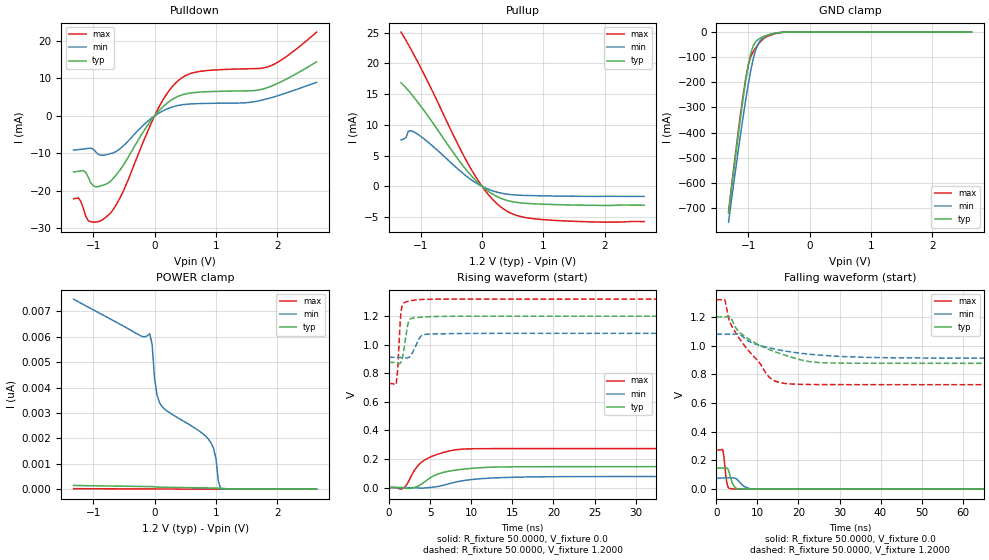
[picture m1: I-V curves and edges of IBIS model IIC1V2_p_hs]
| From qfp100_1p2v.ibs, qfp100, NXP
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[Model] IIC1V2_p_hs
|   Model IIC1V2_p_hs
| This model was characterised for following simulation conditions:
| External (pad) voltage:
|   - Typ: 1.2V,   - Min: 1.08V,   - Max: 1.32V
| Library cells for typ/min/max conditions are connected as defined below:
|  IO - External Pad
|  A - Core Input
|  EN - Output Buffer Enable
|  BOOST - vdde
|  EGP - vdd
|  EHS - vdd
|  ENZI - vdd
|  EPD - gnd
|  EPUN - vdd
|  ZI - NC
|  ZIF - NC
|  gnd - gnd
|  gnde - gnde
|  vdd - vdd
|  vdde - vdde
| All other pins connected to ground
Model_type I/O
Polarity   Non-Inverting
Enable   Active-Low
Vinl =   0.5400V
Vinh =   1.2600V
Vmeas =  0.9000V
Cref =   0.0F
Rref =   1.0000k
Vref =   0.0V
C_comp   3.6473pF   3.5138pF   3.7665pF
|C_comp_pullup   0.9539pF   0.9082pF   0.9728pF
|C_comp_pulldown   2.3399pF   2.4915pF   2.1962pF
[Model Spec]
| variable   typ   min   max
Vinh   0.3600V   0.3240V   0.3960V
Vinl   0.8400V   0.7560V   0.9240V
Vmeas   0.6000V   0.5400V   0.6600V
[Temperature Range]   25.0000   0.1250k   -40.0000
[Voltage Range]   1.2000V   1.0800V   1.3200V
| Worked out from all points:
|   slope of the pulldown table from 0 to 0.18 V, typ, clamps not added: 58.3 ohm
|   slope of the pullup table from 0 to 0.18 V, typ, clamps not added: 138 ohm
|   GND clamp passes 1 mA (typ) near -0.45 V on its own axis
|   rising waveform, R_fixture 50.0000, V_fixture 0.0: 20-80 % time 3.45ns typ, 4.61ns min, 2.73ns max; typ from 0 V to 0.146 V
|   rising waveform, R_fixture 50.0000, V_fixture 1.2000: 20-80 % time 519ps typ, 830ps min, 343ps max; typ from 0.877 V to 1.2 V
|   falling waveform, R_fixture 50.0000, V_fixture 0.0: 20-80 % time 1.02ns typ, 1.79ns min, 624ps max; typ from 0.146 V to 0 V
|   falling waveform, R_fixture 50.0000, V_fixture 1.2000: 20-80 % time 11.4ns typ, 13.9ns min, 8.37ns max; typ from 1.2 V to 0.877 V
[Pulldown]
|Voltage   I(typ)   I(min)   I(max)
-1.32V    -14.96mA   -9.099mA   -22.09mA
-1.24V    -14.75mA   -8.982mA   -21.89mA
-1.16V    -14.56mA   -8.83mA    -24.7mA
-1.04V    -17.82mA   -8.609mA   -28.21mA
-920mV    -18.88mA   -10.21mA   -28.21mA
-720mV    -17.44mA   -10.07mA   -25.94mA
-520mV    -13.41mA   -8.157mA   -20.44mA
80mV      1.521mA    840uA      2.628mA
440mV     5.569mA    2.951mA    10.1mA
760mV     6.377mA    3.307mA    11.92mA
1.84V     7.559mA    4.586mA    13.06mA
2.64V     14.43mA    8.958mA    22.36mA
[Pullup]
|Voltage   I(typ)   I(min)   I(max)
-1.32V    16.87mA    7.562mA    25.11mA
-1.24V    16.04mA    7.944mA    23.76mA
-1.2V     15.58mA    9.001mA    23.05mA
-1.08V    14.1mA     8.693mA    20.85mA
-400mV    4.54mA     2.884mA    6.955mA
-200mV    2.009mA    1.241mA    3.176mA
80mV      -640.3uA   -373.7uA   -1.07mA
320mV     -1.996mA   -1.123mA   -3.467mA
560mV     -2.602mA   -1.412mA   -4.719mA
920mV     -2.876mA   -1.532mA   -5.352mA
1.96V     -3.103mA   -1.628mA   -5.823mA
2.64V     -3.069mA   -1.636mA   -5.736mA
[GND_clamp]
|Voltage   I(typ)   I(min)   I(max)
-1.32V    -720.7mA   -756.4mA   -713.8mA
-1.12V    -330.9mA   -399.5mA   -316.8mA
-1.04V    -192.4mA   -269.2mA   -184.4mA
-1V       -133.6mA   -209.3mA   -133.5mA
-960mV    -86.73mA   -154.7mA   -99.45mA
-920mV    -55.68mA   -108.2mA   -79.01mA
-880mV    -39.01mA   -72.34mA   -63.7mA
-840mV    -29.9mA    -47.99mA   -50.25mA
-760mV    -18.92mA   -23.38mA   -28.31mA
-640mV    -9.212mA   -8.622mA   -12.72mA
-400mV    -328.4uA   -396.6uA   -434.3uA
2.64V     0A         0A         0A
[POWER_clamp]
|Voltage   I(typ)   I(min)   I(max)
-1.32V    146.2pA    7.487nA    20.6pA
-240mV    107.2pA    6.058nA    10.71pA
-80mV     104.3pA    6.128nA    10.43pA
-40mV     105.3pA    5.7nA      9.002pA
0V        87.49pA    4.363nA    8.131pA
80mV      77.4pA     3.412nA    7.54pA
880mV     48.09pA    1.964nA    2.626pA
960mV     44.51pA    1.611nA    2.139pA
1V        42.37pA    1.211nA    1.894pA
1.04V     39.75pA    304.3pA    1.646pA
1.08V     36.09pA    0A         1.394pA
2.64V     0A         0A         0A
[Ramp]
| variable   typ   min   max
dV/dt_r  87.7543m/3.4464n   46.4153m/4.6065n   0.1637/2.7335n
dV/dt_f  0.1940/11.3751n   0.1007/13.8710n   0.3553/8.3673n
R_load = 50.0000
[Rising Waveform]
R_fixture= 50.0000
V_fixture= 0.0
V_fixture_min= 0.0
V_fixture_max= 0.0
|time   V(typ)   V(min)   V(max)
0s        663.7pV    60.46nV    39.17pV
1.735ns   -2.682mV   172.8uV    -4.698mV
2.17ns    -6.221mV   31.22uV    20.88mV
3.005ns   -724.5uV   -2.28mV    111.7mV
3.546ns   10.08mV    -3.777mV   154.7mV
5.333ns   78.4mV     2.145mV    220.8mV
8.076ns   122mV      37.42mV    264mV
11.88ns   140.8mV    64.41mV    272.4mV
33.26ns   146.2mV    77.18mV    272.7mV
1us       146.3mV    77.36mV    272.8mV
[Rising Waveform]
R_fixture= 50.0000
V_fixture= 1.2000
V_fixture_min= 1.0800
V_fixture_max= 1.3200
|time   V(typ)   V(min)   V(max)
0s        876.6mV    912.2mV    727.9mV
925.4ps   873.7mV    912.5mV    744.3mV
1.07ns    870.9mV    912.4mV    833.7mV
1.417ns   872.4mV    910.7mV    1.195V
1.686ns   919.9mV    908.8mV    1.282V
2.223ns   1.121V     906.8mV    1.303V
2.507ns   1.175V     914.8mV    1.307V
3.963ns   1.194V     1.064V     1.317V
5.617ns   1.198V     1.076V     1.319V
1us       1.2V       1.08V      1.32V
[Falling Waveform]
R_fixture= 50.0000
V_fixture= 0.0
V_fixture_min= 0.0
V_fixture_max= 0.0
|time   V(typ)   V(min)   V(max)
0s        146.3mV    77.36mV    272.8mV
1.583ns   146.6mV    77.35mV    269.1mV
1.815ns   147.6mV    77.32mV    228.9mV
2.378ns   149.7mV    77.32mV    73.57mV
2.869ns   135mV      77.95mV    12.66mV
4.132ns   28.89mV    79.27mV    1.543mV
5.749ns   1.763mV    46.03mV    353.1uV
8.143ns   287.7uV    3.769mV    70.4uV
13.48ns   24.82uV    120.4uV    7.14uV
1us       23.59nV    99.24nV    13.67nV
[Falling Waveform]
R_fixture= 50.0000
V_fixture= 1.2000
V_fixture_min= 1.0800
V_fixture_max= 1.3200
|time   V(typ)   V(min)   V(max)
0s        1.2V       1.08V      1.32V
1.968ns   1.2V       1.08V      1.323V
3.029ns   1.203V     1.08V      1.186V
3.948ns   1.169V     1.08V      1.125V
6.283ns   1.078V     1.066V     1.021V
12.91ns   971.7mV    984.4mV    779.2mV
15.66ns   943.4mV    967.9mV    741.4mV
21.16ns   896.8mV    945.1mV    729.9mV
62.12ns   876.8mV    912.9mV    728mV
1us       876.6mV    912.2mV    727.9mV
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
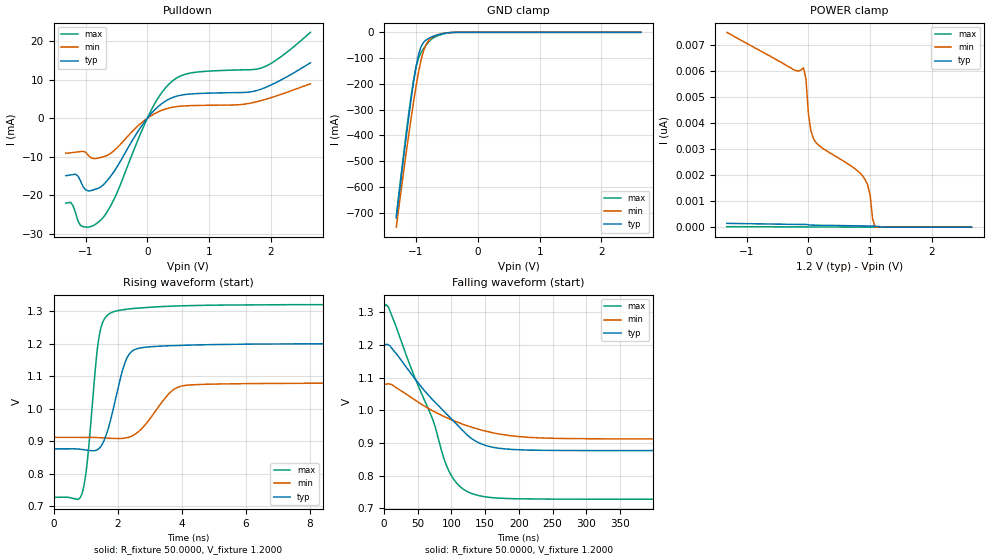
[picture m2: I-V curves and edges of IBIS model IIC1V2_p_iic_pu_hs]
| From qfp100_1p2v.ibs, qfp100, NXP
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[Model] IIC1V2_p_iic_pu_hs
|   Model IIC1V2_p_iic_pu_hs
| This model was characterised for following simulation conditions:
| External (pad) voltage:
|   - Typ: 1.2V,   - Min: 1.08V,   - Max: 1.32V
| Library cells for typ/min/max conditions are connected as defined below:
|  IO - External Pad
|  A - Core Input
|  EN - Output Buffer Enable
|  BOOST - vdde
|  ECS - vdd
|  EGP - gnd
|  ENZI - vdd
|  EPD - gnd
|  EPUN - vdd
|  SSEL - vdd
|  ZI - NC
|  ZIF - NC
|  gnd - gnd
|  gnde - gnde
|  vdd - vdd
|  vdde - vdde
| All other pins connected to ground
Model_type I/O_open_drain
Polarity   Non-Inverting
Enable   Active-Low
Vinl =   0.5400V
Vinh =   1.2600V
Vmeas =  0.9000V
Cref =   0.0F
Rref =   1.0000k
Vref =   1.2000V
C_comp   3.6473pF   3.5138pF   3.7665pF
|C_comp_pullup   0.9537pF   0.9078pF   0.9727pF
|C_comp_pulldown   2.3401pF   2.4920pF   2.1963pF
[Model Spec]
| variable   typ   min   max
Vinh   0.3600V   0.3240V   0.3960V
Vinl   0.8400V   0.7560V   0.9240V
Vmeas   0.6000V   0.5400V   0.6600V
Vref   1.2000V   1.0800V   1.3200V
Cref   0.0F   0.0F   0.0F
Rref   1.0000k   1.0000k   1.0000k
[Temperature Range]   25.0000   0.1250k   -40.0000
[Voltage Range]   1.2000V   1.0800V   1.3200V
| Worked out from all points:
|   slope of the pulldown table from 0 to 0.18 V, typ, clamps not added: 58.3 ohm
|   GND clamp passes 1 mA (typ) near -0.45 V on its own axis
|   rising waveform, R_fixture 50.0000, V_fixture 1.2000: 20-80 % time 494ps typ, 787ps min, 328ps max; typ from 0.877 V to 1.2 V
|   falling waveform, R_fixture 50.0000, V_fixture 1.2000: 20-80 % time 83.3ns typ, 99ns min, 62.7ns max; typ from 1.2 V to 0.877 V
[Pulldown]
|Voltage   I(typ)   I(min)   I(max)
-1.32V    -14.96mA   -9.099mA   -22.09mA
-1.24V    -14.75mA   -8.982mA   -21.89mA
-1.16V    -14.56mA   -8.83mA    -24.7mA
-1.04V    -17.82mA   -8.609mA   -28.21mA
-920mV    -18.88mA   -10.21mA   -28.21mA
-720mV    -17.44mA   -10.07mA   -25.94mA
-520mV    -13.41mA   -8.157mA   -20.44mA
80mV      1.521mA    840uA      2.628mA
440mV     5.569mA    2.951mA    10.1mA
760mV     6.377mA    3.307mA    11.92mA
1.84V     7.559mA    4.586mA    13.06mA
2.64V     14.43mA    8.958mA    22.36mA
[GND_clamp]
|Voltage   I(typ)   I(min)   I(max)
-1.32V    -720.7mA   -756.4mA   -713.8mA
-1.12V    -330.9mA   -399.5mA   -316.8mA
-1.04V    -192.4mA   -269.2mA   -184.4mA
-1V       -133.6mA   -209.3mA   -133.5mA
-960mV    -86.73mA   -154.7mA   -99.45mA
-920mV    -55.68mA   -108.2mA   -79.01mA
-880mV    -39.01mA   -72.34mA   -63.7mA
-840mV    -29.9mA    -47.99mA   -50.25mA
-760mV    -18.92mA   -23.38mA   -28.31mA
-640mV    -9.212mA   -8.622mA   -12.72mA
-400mV    -328.4uA   -396.6uA   -434.3uA
2.64V     0A         0A         0A
[POWER_clamp]
|Voltage   I(typ)   I(min)   I(max)
-1.32V    146.2pA    7.487nA    20.6pA
-240mV    107.2pA    6.058nA    10.71pA
-80mV     104.3pA    6.128nA    10.43pA
-40mV     105.3pA    5.7nA      9.002pA
0V        87.49pA    4.363nA    8.131pA
80mV      77.4pA     3.412nA    7.54pA
880mV     48.09pA    1.964nA    2.626pA
960mV     44.51pA    1.611nA    2.139pA
1V        42.37pA    1.211nA    1.894pA
1.04V     39.75pA    304.3pA    1.646pA
1.08V     36.09pA    0A         1.394pA
2.64V     0A         0A         0A
[Ramp]
| variable   typ   min   max
dV/dt_r  0.1940/0.4944n   0.1007/0.7878n   0.3553/0.3284n
dV/dt_f  0.1940/83.2985n   0.1006/99.0257n   0.3552/62.6594n
R_load = 50.0000
[Rising Waveform]
R_fixture= 50.0000
V_fixture= 1.2000
V_fixture_min= 1.0800
V_fixture_max= 1.3200
|time   V(typ)   V(min)   V(max)
0s        876.6mV    912.2mV    727.9mV
903ps     874.8mV    912.4mV    743.6mV
1.063ns   872.6mV    912.3mV    844.4mV
1.396ns   875.6mV    911.2mV    1.204V
1.672ns   926.9mV    909.9mV    1.286V
2.162ns   1.12V      908.9mV    1.304V
2.467ns   1.178V     917.2mV    1.308V
3.862ns   1.194V     1.065V     1.315V
6.142ns   1.198V     1.077V     1.319V
1us       1.2V       1.08V      1.32V
[Falling Waveform]
R_fixture= 50.0000
V_fixture= 1.2000
V_fixture_min= 1.0800
V_fixture_max= 1.3200
|time   V(typ)   V(min)   V(max)
0s        1.2V       1.08V      1.32V
6.561ns   1.2V       1.081V     1.316V
45.2ns    1.098V     1.032V     1.102V
69.62ns   1.038V     1.002V     985.8mV
95.52ns   983.6mV    975.1mV    817.3mV
112.5ns   947.2mV    961mV      767.4mV
135.3ns   906.9mV    945.2mV    742.1mV
177.8ns   882.4mV    925.3mV    730.9mV
264.1ns   877.4mV    914.1mV    728.5mV
1us       876.7mV    912.3mV    728mV
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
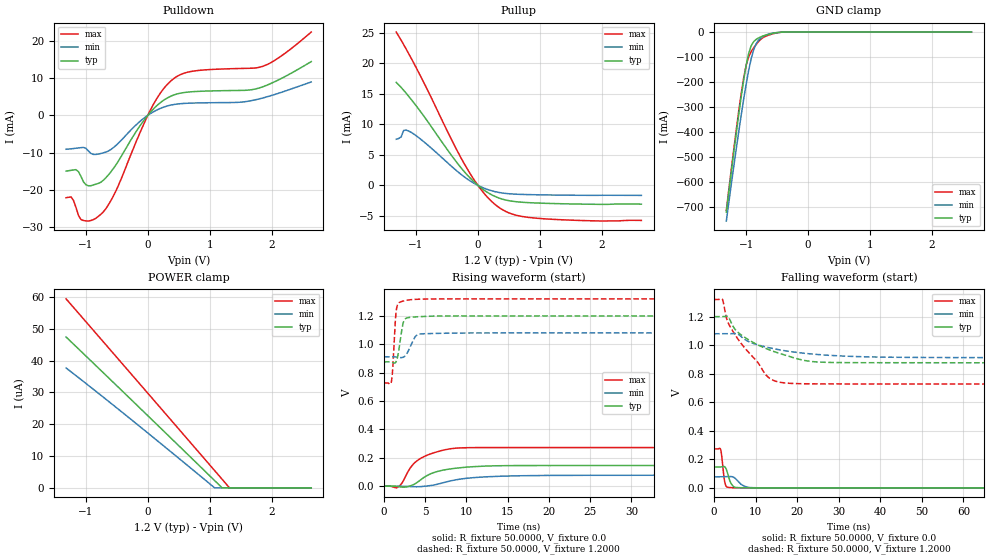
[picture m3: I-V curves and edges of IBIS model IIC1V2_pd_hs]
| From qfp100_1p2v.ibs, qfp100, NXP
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[Model] IIC1V2_pd_hs
|   Model IIC1V2_pd_hs
| This model was characterised for following simulation conditions:
| External (pad) voltage:
|   - Typ: 1.2V,   - Min: 1.08V,   - Max: 1.32V
| Library cells for typ/min/max conditions are connected as defined below:
|  IO - External Pad
|  A - Core Input
|  EN - Output Buffer Enable
|  BOOST - vdde
|  EGP - vdd
|  EHS - vdd
|  ENZI - vdd
|  EPD - vdd
|  EPUN - vdd
|  ZI - NC
|  ZIF - NC
|  gnd - gnd
|  gnde - gnde
|  vdd - vdd
|  vdde - vdde
| All other pins connected to ground
Model_type I/O
Polarity   Non-Inverting
Enable   Active-Low
Vinl =   0.5400V
Vinh =   1.2600V
Vmeas =  0.9000V
Cref =   0.0F
Rref =   1.0000k
Vref =   0.0V
C_comp   3.6164pF   3.4768pF   3.7417pF
|C_comp_pullup   0.9404pF   0.8996pF   0.9549pF
|C_comp_pulldown   2.3238pF   2.4767pF   2.1786pF
[Model Spec]
| variable   typ   min   max
Vinh   0.3600V   0.3240V   0.3960V
Vinl   0.8400V   0.7560V   0.9240V
Vmeas   0.6000V   0.5400V   0.6600V
[Temperature Range]   25.0000   0.1250k   -40.0000
[Voltage Range]   1.2000V   1.0800V   1.3200V
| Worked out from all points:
|   slope of the pulldown table from 0 to 0.18 V, typ, clamps not added: 58.3 ohm
|   slope of the pullup table from 0 to 0.18 V, typ, clamps not added: 138 ohm
|   GND clamp passes 1 mA (typ) near -0.45 V on its own axis
|   rising waveform, R_fixture 50.0000, V_fixture 0.0: 20-80 % time 3.43ns typ, 4.6ns min, 2.73ns max; typ from 0 V to 0.146 V
|   rising waveform, R_fixture 50.0000, V_fixture 1.2000: 20-80 % time 519ps typ, 831ps min, 343ps max; typ from 0.876 V to 1.2 V
|   falling waveform, R_fixture 50.0000, V_fixture 0.0: 20-80 % time 1.02ns typ, 1.79ns min, 624ps max; typ from 0.146 V to 0 V
|   falling waveform, R_fixture 50.0000, V_fixture 1.2000: 20-80 % time 11.4ns typ, 13.8ns min, 8.35ns max; typ from 1.2 V to 0.876 V
[Pulldown]
|Voltage   I(typ)   I(min)   I(max)
-1.32V    -14.96mA   -9.099mA   -22.09mA
-1.24V    -14.75mA   -8.982mA   -21.89mA
-1.16V    -14.56mA   -8.83mA    -24.7mA
-1.04V    -17.82mA   -8.609mA   -28.21mA
-920mV    -18.88mA   -10.21mA   -28.21mA
-720mV    -17.44mA   -10.07mA   -25.94mA
-520mV    -13.41mA   -8.157mA   -20.44mA
80mV      1.521mA    840uA      2.628mA
440mV     5.569mA    2.951mA    10.1mA
760mV     6.377mA    3.307mA    11.92mA
1.84V     7.555mA    4.581mA    13.06mA
2.64V     14.41mA    8.944mA    22.34mA
[Pullup]
|Voltage   I(typ)   I(min)   I(max)
-1.32V    16.86mA    7.551mA    25.1mA
-1.24V    16.02mA    7.934mA    23.74mA
-1.2V     15.57mA    8.991mA    23.04mA
-1.08V    14.09mA    8.684mA    20.84mA
-400mV    4.539mA    2.883mA    6.954mA
-200mV    2.009mA    1.241mA    3.176mA
80mV      -640.3uA   -373.7uA   -1.07mA
320mV     -1.996mA   -1.123mA   -3.467mA
560mV     -2.602mA   -1.412mA   -4.719mA
920mV     -2.876mA   -1.532mA   -5.352mA
1.96V     -3.103mA   -1.628mA   -5.823mA
2.64V     -3.069mA   -1.636mA   -5.736mA
[GND_clamp]
|Voltage   I(typ)   I(min)   I(max)
-1.32V    -720.7mA   -756.5mA   -713.8mA
-1.12V    -330.9mA   -399.5mA   -316.8mA
-1.04V    -192.4mA   -269.2mA   -184.4mA
-1V       -133.6mA   -209.3mA   -133.5mA
-960mV    -86.74mA   -154.7mA   -99.46mA
-920mV    -55.69mA   -108.2mA   -79.02mA
-880mV    -39.02mA   -72.35mA   -63.71mA
-840mV    -29.9mA    -48mA      -50.26mA
-760mV    -18.93mA   -23.39mA   -28.32mA
-640mV    -9.22mA    -8.628mA   -12.73mA
-400mV    -335.3uA   -402.3uA   -442.6uA
2.64V     0A         0A         0A
[POWER_clamp]
|Voltage   I(typ)   I(min)   I(max)
-1.32V    47.4uA     37.67uA    59.39uA
-280mV    27.94uA    21.65uA    36.04uA
1.08V     2.274uA    0A         5.413uA
1.2V      0A         0A         2.707uA
1.32V     0A         0A         0A
2.64V     0A         0A         0A
[Ramp]
| variable   typ   min   max
dV/dt_r  87.6725m/3.4349n   46.3783m/4.5961n   0.1635/2.7265n
dV/dt_f  0.1940/11.3621n   0.1007/13.8533n   0.3552/8.3552n
R_load = 50.0000
[Rising Waveform]
R_fixture= 50.0000
V_fixture= 0.0
V_fixture_min= 0.0
V_fixture_max= 0.0
|time   V(typ)   V(min)   V(max)
0s        642.2pV    57.99nV    36.63pV
1.694ns   -2.271mV   170.4uV    -6.391mV
2.176ns   -6.251mV   22.34uV    21.45mV
3.018ns   -498.8uV   -2.34mV    113mV
3.566ns   10.64mV    -3.8mV     156.1mV
5.371ns   79.64mV    2.414mV    221.6mV
7.998ns   121.3mV    36.42mV    263.3mV
11.68ns   140.2mV    63.76mV    272.1mV
33.54ns   146.1mV    77.12mV    272.4mV
1us       146.1mV    77.3mV     272.5mV
[Rising Waveform]
R_fixture= 50.0000
V_fixture= 1.2000
V_fixture_min= 1.0800
V_fixture_max= 1.3200
|time   V(typ)   V(min)   V(max)
0s        875.8mV    911.4mV    727.2mV
906.2ps   873.2mV    911.8mV    737.4mV
1.073ns   870mV      911.7mV    835.3mV
1.421ns   871.9mV    909.9mV    1.198V
1.691ns   920.7mV    908mV      1.282V
2.233ns   1.123V     906.2mV    1.302V
2.514ns   1.175V     914.6mV    1.306V
3.919ns   1.193V     1.061V     1.316V
5.546ns   1.197V     1.075V     1.318V
1us       1.199V     1.079V     1.319V
[Falling Waveform]
R_fixture= 50.0000
V_fixture= 0.0
V_fixture_min= 0.0
V_fixture_max= 0.0
|time   V(typ)   V(min)   V(max)
0s        146.1mV    77.3mV     272.5mV
1.573ns   146.4mV    77.29mV    269.6mV
1.822ns   147.5mV    77.26mV    227mV
2.382ns   149.5mV    77.26mV    72.39mV
2.876ns   134.4mV    77.9mV     12.14mV
4.152ns   27.81mV    79.14mV    1.429mV
5.775ns   1.661mV    45.1mV     306.5uV
8.109ns   267.7uV    3.938mV    54.94uV
13.4ns    20.27uV    113.7uV    4.825uV
1us       23.56nV    96.75nV    13.66nV
[Falling Waveform]
R_fixture= 50.0000
V_fixture= 1.2000
V_fixture_min= 1.0800
V_fixture_max= 1.3200
|time   V(typ)   V(min)   V(max)
0s        1.199V     1.079V     1.319V
1.975ns   1.199V     1.079V     1.322V
3.038ns   1.202V     1.079V     1.184V
3.832ns   1.175V     1.079V     1.13V
5.997ns   1.083V     1.073V     1.032V
12.59ns   974.3mV    985.8mV    787.2mV
15.19ns   947mV      969.7mV    743.7mV
20.75ns   898.6mV    945.5mV    729.4mV
63.98ns   876mV      912.1mV    727.3mV
1us       875.8mV    911.5mV    727.2mV
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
